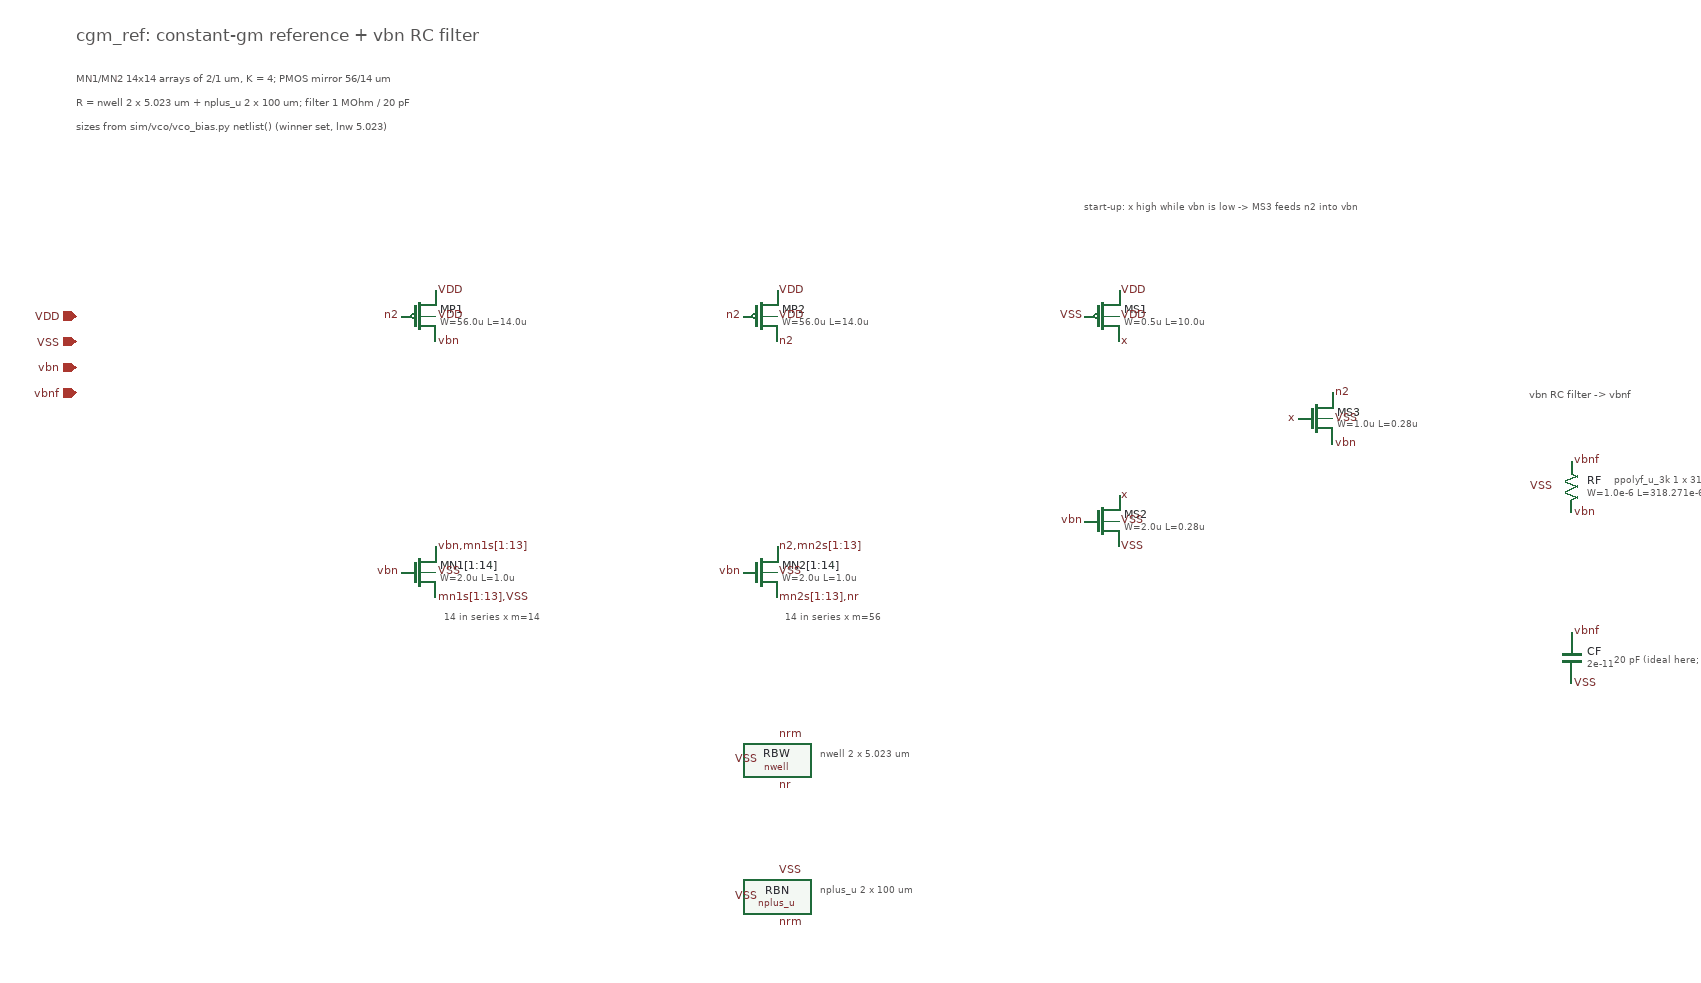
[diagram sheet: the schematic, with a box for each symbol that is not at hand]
v {xschem version=3.4.5 file_version=1.2
}
G {}
K {}
V {}
S {}
E {}
T {14 in series x m=14} 30 40 0 0 0.3 0.3 {}
T {14 in series x m=56} 430 40 0 0 0.3 0.3 {}
T {nwell 2 x 5.023 um} 470 200 0 0 0.3 0.3 {}
T {nplus_u 2 x 100 um} 470 360 0 0 0.3 0.3 {}
T {start-up: x high while vbn is low -> MS3 feeds n2 into vbn} 780 -440 0 0 0.3 0.3 {}
T {ppolyf_u_3k 1 x 318.3 um = 1 MOhm} 1400 -120 0 0 0.3 0.3 {}
T {20 pF (ideal here; MOS cap on silicon)} 1400 90 0 0 0.3 0.3 {}
T {vbn RC filter -> vbnf} 1300 -220 0 0 0.35 0.35 {}
T {cgm_ref: constant-gm reference + vbn RC filter} -400 -640 0 0 0.6 0.6 {}
T {MN1/MN2 14x14 arrays of 2/1 um, K = 4; PMOS mirror 56/14 um} -400 -590 0 0 0.35 0.35 {}
T {R = nwell 2 x 5.023 um + nplus_u 2 x 100 um; filter 1 MOhm / 20 pF} -400 -562 0 0 0.35 0.35 {}
T {sizes from sim/vco/vco_bias.py netlist() (winner set, lnw 5.023)} -400 -534 0 0 0.35 0.35 {}
C {devices/iopin.sym} -400 -300 0 0 {name=p40
lab=VDD}
C {devices/iopin.sym} -400 -270 0 0 {name=p41
lab=VSS}
C {devices/iopin.sym} -400 -240 0 0 {name=p42
lab=vbn}
C {devices/iopin.sym} -400 -210 0 0 {name=p43
lab=vbnf}
C {symbols/nfet_03v3.sym} 0 0 0 0 {name=MN1[1:14]
L=1.0u
W=2.0u
nf=1
m=14
ad=1.0p
as=1.0p
pd=5.0u
ps=5.0u
nrd=0
nrs=0
sa=0
sb=0
sd=0
model=nfet_03v3
spiceprefix=X}
C {devices/lab_pin.sym} 20 -30 0 1 {name=p1
sig_type=std_logic
lab=vbn,mn1s[1:13]}
C {devices/lab_pin.sym} -20 0 0 0 {name=p2
sig_type=std_logic
lab=vbn}
C {devices/lab_pin.sym} 20 30 0 1 {name=p3
sig_type=std_logic
lab=mn1s[1:13],VSS}
C {devices/lab_pin.sym} 20 0 0 1 {name=p4
sig_type=std_logic
lab=VSS}
C {symbols/nfet_03v3.sym} 400 0 0 0 {name=MN2[1:14]
L=1.0u
W=2.0u
nf=1
m=56
ad=1.0p
as=1.0p
pd=5.0u
ps=5.0u
nrd=0
nrs=0
sa=0
sb=0
sd=0
model=nfet_03v3
spiceprefix=X}
C {devices/lab_pin.sym} 420 -30 0 1 {name=p5
sig_type=std_logic
lab=n2,mn2s[1:13]}
C {devices/lab_pin.sym} 380 0 0 0 {name=p6
sig_type=std_logic
lab=vbn}
C {devices/lab_pin.sym} 420 30 0 1 {name=p7
sig_type=std_logic
lab=mn2s[1:13],nr}
C {devices/lab_pin.sym} 420 0 0 1 {name=p8
sig_type=std_logic
lab=VSS}
C {symbols/pfet_03v3.sym} 0 -300 0 0 {name=MP1
L=14.0u
W=56.0u
nf=1
m=1
ad=28.0p
as=28.0p
pd=113.0u
ps=113.0u
nrd=0
nrs=0
sa=0
sb=0
sd=0
model=pfet_03v3
spiceprefix=X}
C {devices/lab_pin.sym} 20 -270 0 1 {name=p9
sig_type=std_logic
lab=vbn}
C {devices/lab_pin.sym} -20 -300 0 0 {name=p10
sig_type=std_logic
lab=n2}
C {devices/lab_pin.sym} 20 -330 0 1 {name=p11
sig_type=std_logic
lab=VDD}
C {devices/lab_pin.sym} 20 -300 0 1 {name=p12
sig_type=std_logic
lab=VDD}
C {symbols/pfet_03v3.sym} 400 -300 0 0 {name=MP2
L=14.0u
W=56.0u
nf=1
m=1
ad=28.0p
as=28.0p
pd=113.0u
ps=113.0u
nrd=0
nrs=0
sa=0
sb=0
sd=0
model=pfet_03v3
spiceprefix=X}
C {devices/lab_pin.sym} 420 -270 0 1 {name=p13
sig_type=std_logic
lab=n2}
C {devices/lab_pin.sym} 380 -300 0 0 {name=p14
sig_type=std_logic
lab=n2}
C {devices/lab_pin.sym} 420 -330 0 1 {name=p15
sig_type=std_logic
lab=VDD}
C {devices/lab_pin.sym} 420 -300 0 1 {name=p16
sig_type=std_logic
lab=VDD}
C {symbols/nwell.sym} 420 220 0 0 {name=RBW
W=2.0e-6
L=5.023e-6
model=nwell
spiceprefix=X
m=1}
C {devices/lab_pin.sym} 420 250 0 1 {name=p17
sig_type=std_logic
lab=nr}
C {devices/lab_pin.sym} 420 190 0 1 {name=p18
sig_type=std_logic
lab=nrm}
C {devices/lab_pin.sym} 400 220 0 0 {name=p19
sig_type=std_logic
lab=VSS}
C {symbols/nplus_u.sym} 420 380 0 0 {name=RBN
W=2.0e-6
L=100.0e-6
model=nplus_u
spiceprefix=X
m=1}
C {devices/lab_pin.sym} 420 410 0 1 {name=p20
sig_type=std_logic
lab=nrm}
C {devices/lab_pin.sym} 420 350 0 1 {name=p21
sig_type=std_logic
lab=VSS}
C {devices/lab_pin.sym} 400 380 0 0 {name=p22
sig_type=std_logic
lab=VSS}
C {symbols/pfet_03v3.sym} 800 -300 0 0 {name=MS1
L=10.0u
W=0.5u
nf=1
m=1
ad=0.25p
as=0.25p
pd=2.0u
ps=2.0u
nrd=0
nrs=0
sa=0
sb=0
sd=0
model=pfet_03v3
spiceprefix=X}
C {devices/lab_pin.sym} 820 -270 0 1 {name=p23
sig_type=std_logic
lab=x}
C {devices/lab_pin.sym} 780 -300 0 0 {name=p24
sig_type=std_logic
lab=VSS}
C {devices/lab_pin.sym} 820 -330 0 1 {name=p25
sig_type=std_logic
lab=VDD}
C {devices/lab_pin.sym} 820 -300 0 1 {name=p26
sig_type=std_logic
lab=VDD}
C {symbols/nfet_03v3.sym} 800 -60 0 0 {name=MS2
L=0.28u
W=2.0u
nf=1
m=1
ad=1.0p
as=1.0p
pd=5.0u
ps=5.0u
nrd=0
nrs=0
sa=0
sb=0
sd=0
model=nfet_03v3
spiceprefix=X}
C {devices/lab_pin.sym} 820 -90 0 1 {name=p27
sig_type=std_logic
lab=x}
C {devices/lab_pin.sym} 780 -60 0 0 {name=p28
sig_type=std_logic
lab=vbn}
C {devices/lab_pin.sym} 820 -30 0 1 {name=p29
sig_type=std_logic
lab=VSS}
C {devices/lab_pin.sym} 820 -60 0 1 {name=p30
sig_type=std_logic
lab=VSS}
C {symbols/nfet_03v3.sym} 1050 -180 0 0 {name=MS3
L=0.28u
W=1.0u
nf=1
m=1
ad=0.5p
as=0.5p
pd=3.0u
ps=3.0u
nrd=0
nrs=0
sa=0
sb=0
sd=0
model=nfet_03v3
spiceprefix=X}
C {devices/lab_pin.sym} 1070 -210 0 1 {name=p31
sig_type=std_logic
lab=n2}
C {devices/lab_pin.sym} 1030 -180 0 0 {name=p32
sig_type=std_logic
lab=x}
C {devices/lab_pin.sym} 1070 -150 0 1 {name=p33
sig_type=std_logic
lab=vbn}
C {devices/lab_pin.sym} 1070 -180 0 1 {name=p34
sig_type=std_logic
lab=VSS}
C {symbols/ppolyf_u_3k.sym} 1350 -100 0 0 {name=RF
W=1.0e-6
L=318.271e-6
model=ppolyf_u_3k
spiceprefix=X
m=1}
C {devices/lab_pin.sym} 1350 -70 0 1 {name=p35
sig_type=std_logic
lab=vbn}
C {devices/lab_pin.sym} 1350 -130 0 1 {name=p36
sig_type=std_logic
lab=vbnf}
C {devices/lab_pin.sym} 1330 -100 0 0 {name=p37
sig_type=std_logic
lab=VSS}
C {devices/capa.sym} 1350 100 0 0 {name=CF
value=2e-11
m=1}
C {devices/lab_pin.sym} 1350 70 0 1 {name=p38
sig_type=std_logic
lab=vbnf}
C {devices/lab_pin.sym} 1350 130 0 1 {name=p39
sig_type=std_logic
lab=VSS}
